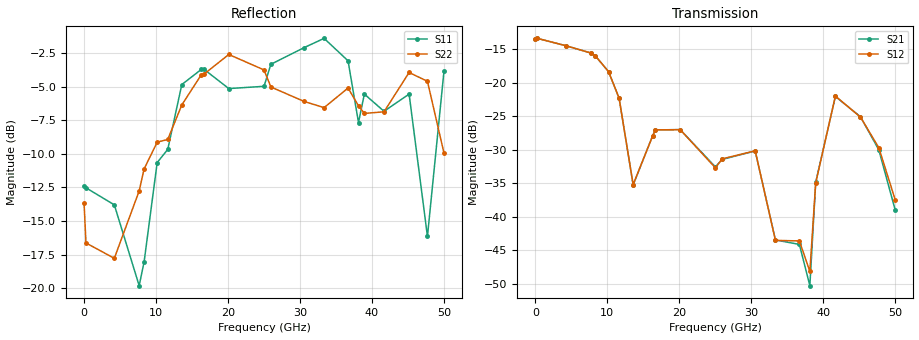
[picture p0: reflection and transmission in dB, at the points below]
!Keysight Technologies,N5245B,MY58422270,A.16.20.02
!Date: Thursday, March 05, 2026 00:58:16
!Correction: S11(C  2-Port  )
!S21(C  2-Port  )
!S12(C  2-Port  )
!S22(C  2-Port  )
!S2P File: Measurements: S11, S21, S12, S22:
# Hz S  dB  R 50
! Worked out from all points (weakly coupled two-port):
!   3201 points, 10 MHz to 50 GHz, reference 50 ohm
!   highest |S21| = -13.41 dB at 275.6 MHz (marker M1); lowest = -50.3 dB at 38.13 GHz (marker M2)
!   lowest |S11| = -19.8 dB at 7.665 GHz (marker M3), VSWR 1.23, Z = 40.8 - j1.13 ohm
!   |S11| at or under -10 dB: start of sweep to 10.39 GHz; 46.73 GHz to 48.26 GHz (1.53 GHz wide, 3.22 % of centre)
!   |S22| runs from -18.6 to -2.4 dB; largest |S21 - S12| = 0.0082
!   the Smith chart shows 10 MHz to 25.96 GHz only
!   S11 on the Smith chart (normalised r, x): 10 MHz: 1.63, -0.04; 10.16 GHz: 0.55, +0.09; 13.59 GHz: 0.94, +1.35; 16.3 GHz: 1.88, -2.19; 20.12 GHz: 0.37, -0.52; 25.96 GHz: 0.20, +0.18
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1e7  -12.38 -2.9  -13.51 4.2  -13.50 3.1  -13.67 36.1
2.755719e8  -12.53 -9.7  -13.41 -11.1  -13.41 -11.3  -16.64 -8.7
4.212284e9  -13.80 -132.5  -14.50 -173.6  -14.50 -173.5  -17.78 -135.8
7.664719e9  -19.82 -172.3  -15.58 34.9  -15.58 34.9  -12.76 -145.5
8.352081e9  -18.04 -162.7  -16.06 3.2  -16.05 3.3  -11.12 -161.6
1.016422e10  -10.65 164.7  -18.37 -80.5  -18.37 -80.4  -9.13 138.8
1.163268e10  -9.67 119.2  -22.33 -147.1  -22.33 -147.2  -8.93 65.9
1.358541e10  -4.84 57.6  -35.28 151.3  -35.23 151.0  -6.36 -38.8
1.630362e10  -3.71 -30.9  -27.91 174.3  -27.94 174.3  -4.10 -134.5
1.667854e10  -3.71 -42.0  -27.08 161.0  -27.06 160.4  -4.06 -142.9
2.011535e10  -5.14 -119.5  -27.02 46.4  -27.04 46.6  -2.60 156.2
2.5005e10  -4.97 174.5  -32.59 -65.3  -32.73 -64.4  -3.75 70.3
2.595793e10  -3.33 158.3  -31.47 -81.0  -31.39 -80.2  -5.02 46.8
3.053514e10  -2.10 80.4  -30.22 125.4  -30.19 125.2  -6.09 -50.7
3.334708e10  -1.40 35.7  -43.50 -3.8  -43.56 -2.3  -6.56 -132.6
3.667454e10  -3.07 -30.8  -44.16 104.4  -43.64 107.8  -5.10 159.7
3.812738e10  -7.67 -23.2  -50.32 97.7  -48.20 -73.4  -6.42 133.1
3.893971e10  -5.55 -30.1  -34.89 92.9  -34.97 95.9  -6.99 133.0
4.167354e10  -6.83 -55.0  -22.08 -59.9  -22.02 -59.8  -6.87 112.5
4.515722e10  -5.55 -102.5  -25.11 88.1  -25.16 88.2  -3.94 74.6
4.770358e10  -16.15 71.6  -30.04 -17.6  -29.72 -17.1  -4.60 41.2
5e10  -3.84 -72.6  -39.09 -111.1  -37.57 -119.9  -9.94 7.1
